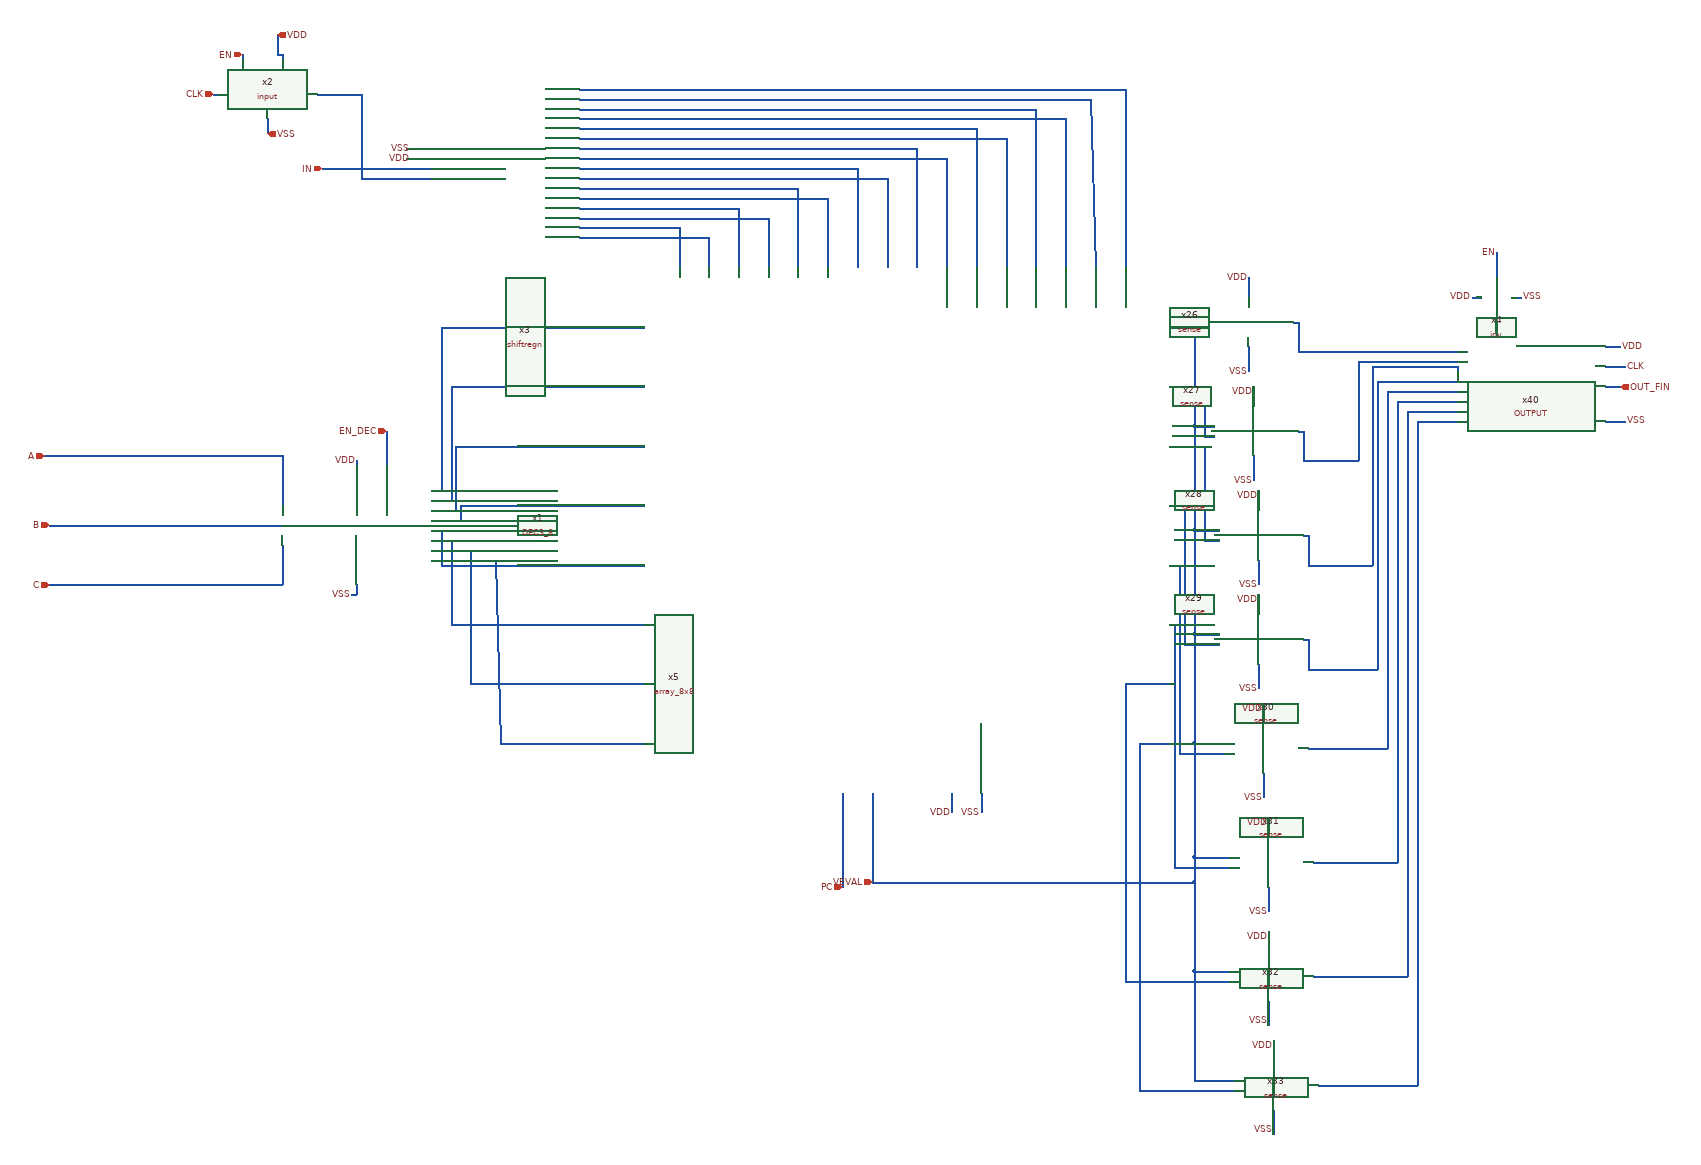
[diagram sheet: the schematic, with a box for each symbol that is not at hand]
v {xschem version=3.4.6 file_version=1.2}
G {}
K {}
V {}
S {}
E {}
N 7730 20 7730 40 {lab=#net1}
N 7950 70 7980 70 {lab=VDD}
N 7950 110 7990 110 {lab=CLK}
N 7950 150 7980 150 {lab=OUT_FIN}
N 7950 220 7990 220 {lab=VSS}
N 6690 970 6690 1010 {lab=VSS}
N 5880 -150 6140 -150 {lab=#net2}
N 6140 -150 6140 -90 {lab=#net2}
N 5880 -170 6080 -170 {lab=#net3}
N 6080 -170 6080 -90 {lab=#net3}
N 5880 -190 6260 -190 {lab=#net4}
N 6260 -190 6260 -90 {lab=#net4}
N 5880 -210 6200 -210 {lab=#net5}
N 6200 -210 6200 -90 {lab=#net5}
N 5880 -230 6380 -230 {lab=#net6}
N 6380 -230 6380 -90 {lab=#net6}
N 5880 -250 6320 -250 {lab=#net7}
N 6320 -250 6320 -90 {lab=#net7}
N 5880 -270 6500 -270 {lab=#net8}
N 6500 -270 6500 -90 {lab=#net8}
N 5880 -290 6440 -290 {lab=#net9}
N 6440 -290 6440 -90 {lab=#net9}
N 5880 -310 6620 -310 {lab=#net10}
N 6620 -310 6620 -90 {lab=#net10}
N 5880 -330 6560 -330 {lab=#net11}
N 6560 -330 6560 -90 {lab=#net11}
N 5880 -350 6740 -350 {lab=#net12}
N 6740 -350 6740 -90 {lab=#net12}
N 5880 -370 6680 -370 {lab=#net13}
N 6680 -370 6680 -90 {lab=#net13}
N 5880 -390 6860 -390 {lab=#net14}
N 6860 -390 6860 -90 {lab=#net14}
N 5880 -410 6800 -410 {lab=#net15}
N 6800 -410 6800 -90 {lab=#net15}
N 5880 -450 6980 -450 {lab=#net16}
N 6980 -450 6980 -90 {lab=#net16}
N 5880 -430 6910 -430 {lab=#net17}
N 6910 -430 6920 -90 {lab=#net17}
N 5530 -330 5580 -330 {lab=VSS}
N 5530 -310 5580 -310 {lab=VDD}
N 5360 -290 5580 -290 {lab=IN}
N 5440 -440 5440 -270 {lab=#net18}
N 5440 -270 5580 -270 {lab=#net18}
N 7070 30 7150 30 {lab=#net19}
N 7230 -70 7230 -30 {lab=VDD}
N 7230 70 7230 120 {lab=VSS}
N 7330 80 7650 80 {lab=#net20}
N 7330 20 7330 80 {lab=#net20}
N 7320 20 7330 20 {lab=#net20}
N 7240 150 7240 190 {lab=VDD}
N 7240 290 7240 340 {lab=VSS}
N 7340 240 7340 300 {lab=#net21}
N 7330 240 7340 240 {lab=#net21}
N 7250 360 7250 400 {lab=VDD}
N 7250 500 7250 550 {lab=VSS}
N 7350 450 7350 510 {lab=#net22}
N 7340 450 7350 450 {lab=#net22}
N 7250 570 7250 610 {lab=VDD}
N 7250 710 7250 760 {lab=VSS}
N 7350 660 7350 720 {lab=#net23}
N 7340 660 7350 660 {lab=#net23}
N 7260 790 7260 830 {lab=VDD}
N 7260 930 7260 980 {lab=VSS}
N 7350 880 7510 880 {lab=#net24}
N 7270 1020 7270 1060 {lab=VDD}
N 7270 1160 7270 1210 {lab=VSS}
N 7360 1110 7530 1110 {lab=#net25}
N 7270 1250 7270 1290 {lab=VDD}
N 7270 1390 7270 1440 {lab=VSS}
N 7360 1340 7550 1340 {lab=#net26}
N 7280 1470 7280 1510 {lab=VDD}
N 7280 1610 7280 1660 {lab=VSS}
N 7370 1560 7570 1560 {lab=#net27}
N 7120 10 7150 10 {lab=VEVAL}
N 7120 230 7160 230 {lab=VEVAL}
N 7120 440 7170 440 {lab=VEVAL}
N 7120 230 7120 440 {lab=VEVAL}
N 7120 10 7120 230 {lab=VEVAL}
N 7120 440 7120 650 {lab=VEVAL}
N 7120 650 7170 650 {lab=VEVAL}
N 7120 650 7120 870 {lab=VEVAL}
N 7120 870 7180 870 {lab=VEVAL}
N 7120 870 7120 1100 {lab=VEVAL}
N 7120 1100 7190 1100 {lab=VEVAL}
N 7120 1150 7120 1330 {lab=VEVAL}
N 7120 1330 7190 1330 {lab=VEVAL}
N 6410 970 6410 1160 {lab=PC}
N 6470 970 6470 1150 {lab=VEVAL}
N 7450 100 7650 100 {lab=#net21}
N 7450 100 7450 300 {lab=#net21}
N 7340 300 7450 300 {lab=#net21}
N 7350 510 7480 510 {lab=#net22}
N 7480 110 7480 510 {lab=#net22}
N 7480 110 7650 110 {lab=#net22}
N 7650 110 7650 120 {lab=#net22}
N 7490 140 7650 140 {lab=#net23}
N 7490 140 7490 720 {lab=#net23}
N 7350 720 7490 720 {lab=#net23}
N 7510 160 7650 160 {lab=#net24}
N 7510 160 7510 880 {lab=#net24}
N 7530 180 7650 180 {lab=#net25}
N 7530 180 7530 1110 {lab=#net25}
N 7550 200 7650 200 {lab=#net26}
N 7550 200 7550 1340 {lab=#net26}
N 7570 220 7650 220 {lab=#net27}
N 7570 220 7570 1560 {lab=#net27}
N 7070 150 7140 150 {lab=#net28}
N 7140 150 7140 250 {lab=#net28}
N 7140 250 7160 250 {lab=#net28}
N 7070 270 7140 270 {lab=#net29}
N 7140 270 7140 460 {lab=#net29}
N 7140 460 7170 460 {lab=#net29}
N 7070 390 7100 390 {lab=#net30}
N 7100 390 7100 670 {lab=#net30}
N 7100 670 7170 670 {lab=#net30}
N 7070 510 7090 510 {lab=#net31}
N 7090 510 7090 890 {lab=#net31}
N 7090 890 7180 890 {lab=#net31}
N 7070 630 7080 630 {lab=#net32}
N 7080 630 7080 1120 {lab=#net32}
N 7080 1120 7190 1120 {lab=#net32}
N 6980 750 7070 750 {lab=#net33}
N 6980 750 6980 1350 {lab=#net33}
N 6980 1350 7190 1350 {lab=#net33}
N 7010 870 7070 870 {lab=#net34}
N 7010 870 7010 1570 {lab=#net34}
N 7010 1570 7200 1570 {lab=#net34}
N 7120 1330 7120 1550 {lab=VEVAL}
N 7120 1550 7200 1550 {lab=VEVAL}
N 4800 290 5280 290 {lab=A}
N 4810 430 5280 430 {lab=B}
N 4810 550 5280 550 {lab=C}
N 5430 550 5430 570 {lab=VSS}
N 5420 570 5430 570 {lab=VSS}
N 5430 300 5430 310 {lab=VDD}
N 5600 30 6010 30 {lab=#net35}
N 5600 30 5600 360 {lab=#net35}
N 5580 360 5600 360 {lab=#net35}
N 5620 150 6010 150 {lab=#net36}
N 5620 150 5620 380 {lab=#net36}
N 5580 380 5620 380 {lab=#net36}
N 5630 270 6010 270 {lab=#net37}
N 5630 270 5630 400 {lab=#net37}
N 5580 400 5630 400 {lab=#net37}
N 5640 390 6010 390 {lab=#net38}
N 5640 390 5640 420 {lab=#net38}
N 5580 420 5640 420 {lab=#net38}
N 5600 510 6010 510 {lab=#net39}
N 5600 440 5600 510 {lab=#net39}
N 5580 440 5600 440 {lab=#net39}
N 5620 630 6010 630 {lab=#net40}
N 5620 460 5620 630 {lab=#net40}
N 5580 460 5620 460 {lab=#net40}
N 5660 750 6010 750 {lab=#net41}
N 5660 480 5660 750 {lab=#net41}
N 5580 480 5660 480 {lab=#net41}
N 5720 870 6010 870 {lab=#net42}
N 5710 500 5720 870 {lab=#net42}
N 5580 500 5710 500 {lab=#net42}
N 5140 -440 5150 -440 {lab=CLK}
N 5280 -520 5280 -510 {lab=VDD}
N 5200 -520 5200 -510 {lab=EN}
N 5250 -390 5250 -360 {lab=VSS}
N 5350 -440 5440 -440 {lab=#net18}
N 6470 1150 7120 1150 {lab=VEVAL}
N 7120 1100 7120 1150 {lab=VEVAL}
N 5270 -560 5270 -520 {lab=VDD}
N 5270 -520 5280 -520 {lab=VDD}
N 5490 240 5490 310 {lab=EN_DEC}
N 7730 -120 7730 -70 {lab=EN}
N 7680 -30 7700 -30 {lab=VDD}
N 7760 -30 7780 -30 {lab=VSS}
N 5280 290 5280 390 {lab=A}
N 5280 470 5280 550 {lab=C}
N 6630 970 6630 1010 {lab=VDD}
C {shiftregn.sym} 5730 -280 0 0 {name=x3}
C {OUTPUT.sym} 7800 150 0 0 {name=x40}
C {lab_wire.sym} 7980 70 0 1 {name=p13 sig_type=std_logic lab=VDD

}
C {lab_wire.sym} 7990 110 0 1 {name=p95 sig_type=std_logic lab=CLK



}
C {array_8x8.sym} 5670 1140 0 0 {name=x5}
C {lab_wire.sym} 6690 1010 0 0 {name=p100 sig_type=std_logic lab=VSS
}
C {lab_wire.sym} 6630 1010 0 0 {name=p101 sig_type=std_logic lab=VDD

}
C {lab_wire.sym} 5540 -330 0 0 {name=p104 sig_type=std_logic lab=VSS
}
C {lab_wire.sym} 5540 -310 0 0 {name=p105 sig_type=std_logic lab=VDD

}
C {sense.sym} 7300 20 0 0 {name=x26}
C {sense.sym} 7310 240 0 0 {name=x27}
C {lab_wire.sym} 7240 160 0 0 {name=p114 sig_type=std_logic lab=VDD

}
C {sense.sym} 7320 450 0 0 {name=x28}
C {lab_wire.sym} 7250 370 0 0 {name=p116 sig_type=std_logic lab=VDD

}
C {sense.sym} 7320 660 0 0 {name=x29}
C {lab_wire.sym} 7250 580 0 0 {name=p118 sig_type=std_logic lab=VDD

}
C {sense.sym} 7330 880 0 0 {name=x30}
C {lab_wire.sym} 7260 800 0 0 {name=p120 sig_type=std_logic lab=VDD

}
C {sense.sym} 7340 1110 0 0 {name=x31}
C {lab_wire.sym} 7270 1030 0 0 {name=p122 sig_type=std_logic lab=VDD

}
C {sense.sym} 7340 1340 0 0 {name=x32}
C {lab_wire.sym} 7270 1260 0 0 {name=p124 sig_type=std_logic lab=VDD

}
C {sense.sym} 7350 1560 0 0 {name=x33}
C {lab_wire.sym} 7280 1650 0 0 {name=p125 sig_type=std_logic lab=VSS
}
C {lab_wire.sym} 7280 1480 0 0 {name=p126 sig_type=std_logic lab=VDD

}
C {lab_wire.sym} 5420 570 0 0 {name=p136 sig_type=std_logic lab=VSS
}
C {lab_wire.sym} 5430 300 0 0 {name=p137 sig_type=std_logic lab=VDD

}
C {ipin.sym} 5200 -520 0 0 {name=p2 lab=EN}
C {iopin.sym} 5270 -560 0 1 {name=p3 lab=VDD}
C {iopin.sym} 5250 -360 0 1 {name=p4 lab=VSS}
C {ipin.sym} 5140 -440 0 0 {name=p5 lab=CLK}
C {ipin.sym} 4800 290 0 0 {name=p6 lab=A}
C {ipin.sym} 4810 430 0 0 {name=p7 lab=B}
C {ipin.sym} 4810 550 0 0 {name=p8 lab=C}
C {ipin.sym} 5360 -290 0 0 {name=p14 lab=IN}
C {ipin.sym} 6410 1160 0 0 {name=p1 lab=PC}
C {ipin.sym} 6470 1150 3 0 {name=p15 lab=VEVAL}
C {ipin.sym} 5490 240 0 0 {name=p16 lab=EN_DEC}
C {lab_wire.sym} 7230 120 0 0 {name=p10 sig_type=std_logic lab=VSS
}
C {lab_wire.sym} 7240 340 0 0 {name=p11 sig_type=std_logic lab=VSS
}
C {lab_wire.sym} 7250 550 0 0 {name=p12 sig_type=std_logic lab=VSS
}
C {lab_wire.sym} 7250 760 0 0 {name=p17 sig_type=std_logic lab=VSS
}
C {lab_wire.sym} 7260 980 0 0 {name=p18 sig_type=std_logic lab=VSS
}
C {lab_wire.sym} 7270 1210 0 0 {name=p19 sig_type=std_logic lab=VSS
}
C {lab_wire.sym} 7270 1430 0 0 {name=p20 sig_type=std_logic lab=VSS
}
C {lab_wire.sym} 7990 220 0 1 {name=p21 sig_type=std_logic lab=VSS
}
C {opin.sym} 7980 150 0 0 {name=p22 lab=OUT_FIN}
C {DEC3_8.sym} 5430 430 0 0 {name=x1}
C {input.sym} 5300 -440 0 0 {name=x2}
C {lab_wire.sym} 7230 -70 0 0 {name=p9 sig_type=std_logic lab=VDD

}
C {lab_wire.sym} 7680 -30 0 0 {name=p23 sig_type=std_logic lab=VDD

}
C {lab_wire.sym} 7780 -30 0 1 {name=p24 sig_type=std_logic lab=VSS
}
C {inv.sym} 7820 10 3 1 {name=x4}
C {lab_wire.sym} 7730 -120 0 0 {name=p25 sig_type=std_logic lab=EN

}
